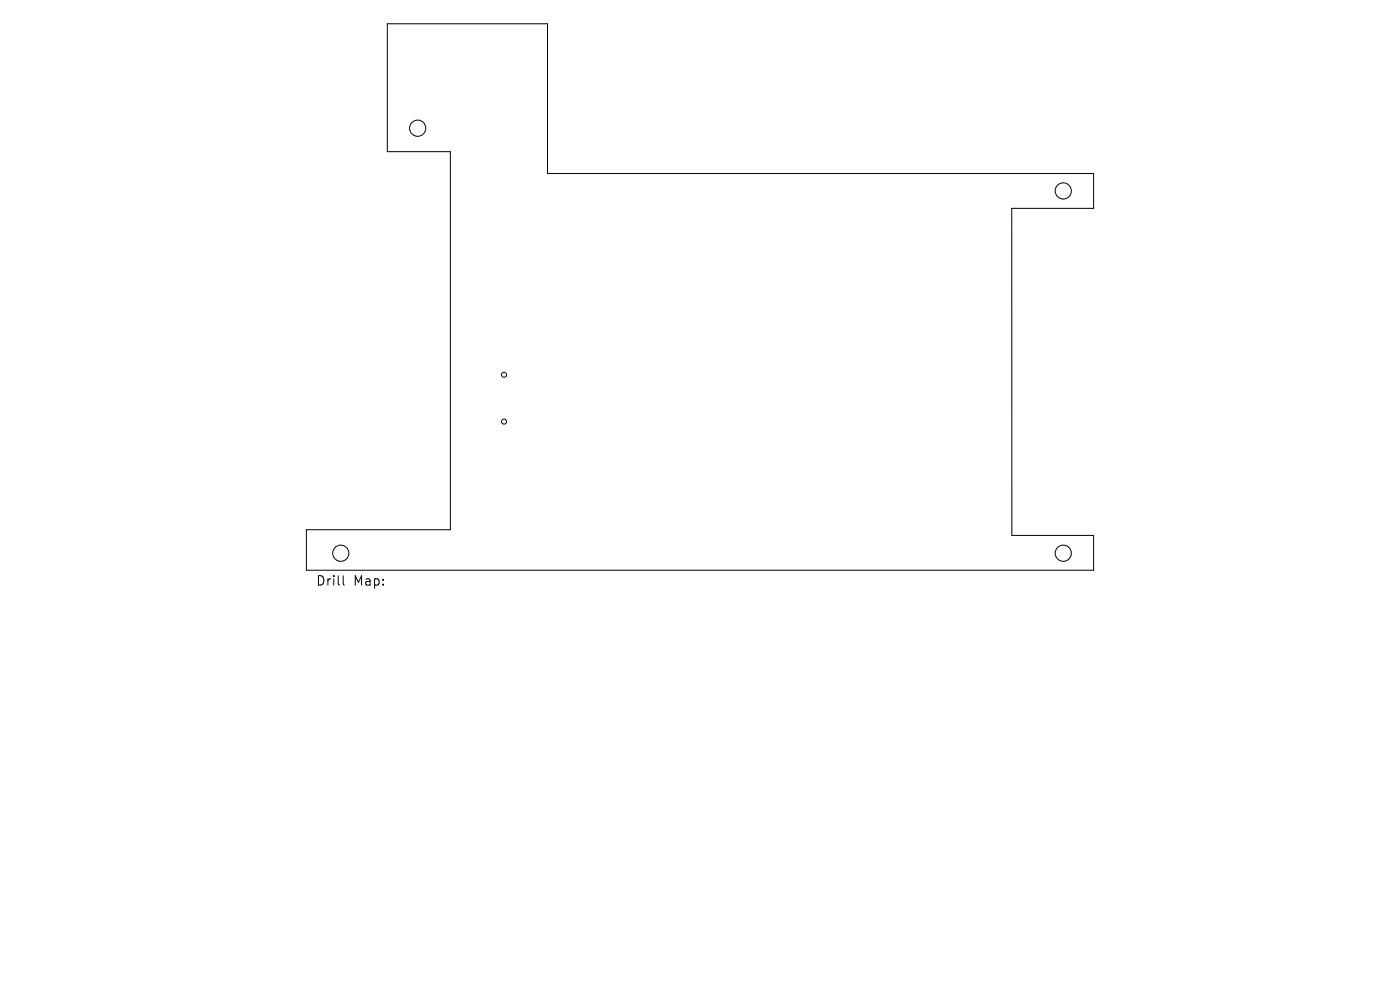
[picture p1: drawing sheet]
<svg xmlns="http://www.w3.org/2000/svg" width="297mm" height="210mm" viewBox="0 0 297 210" stroke-linecap="round" stroke-linejoin="round" font-family="sans-serif">
<defs><g id="words">
<g font-size="2.8">
<text x="67" y="124.5">Drill</text>
<text x="75" y="124.5">Map:</text>
</g>
</g></defs>
<g fill="none" stroke="#000" stroke-width=".21">
<path d="M82.2 5h34v31.8h115.8v7.4h-17.4l.1 69.4h17.3v7.4h-167v-8.6h30.5v-80.2h-13.3zM72.8 122.1v1.7l.3 .3"/>
<circle cx="88.6" cy="27.2" r="1.72"/>
<circle cx="225.6" cy="40.5" r="1.72"/>
<circle cx="106.9" cy="79.5" r=".54"/>
<circle cx="106.9" cy="89.4" r=".54"/>
<circle cx="72.3" cy="117.4" r="1.72"/>
<circle cx="225.6" cy="117.4" r="1.72"/>
</g>
<use href="#words"/>
</svg>
